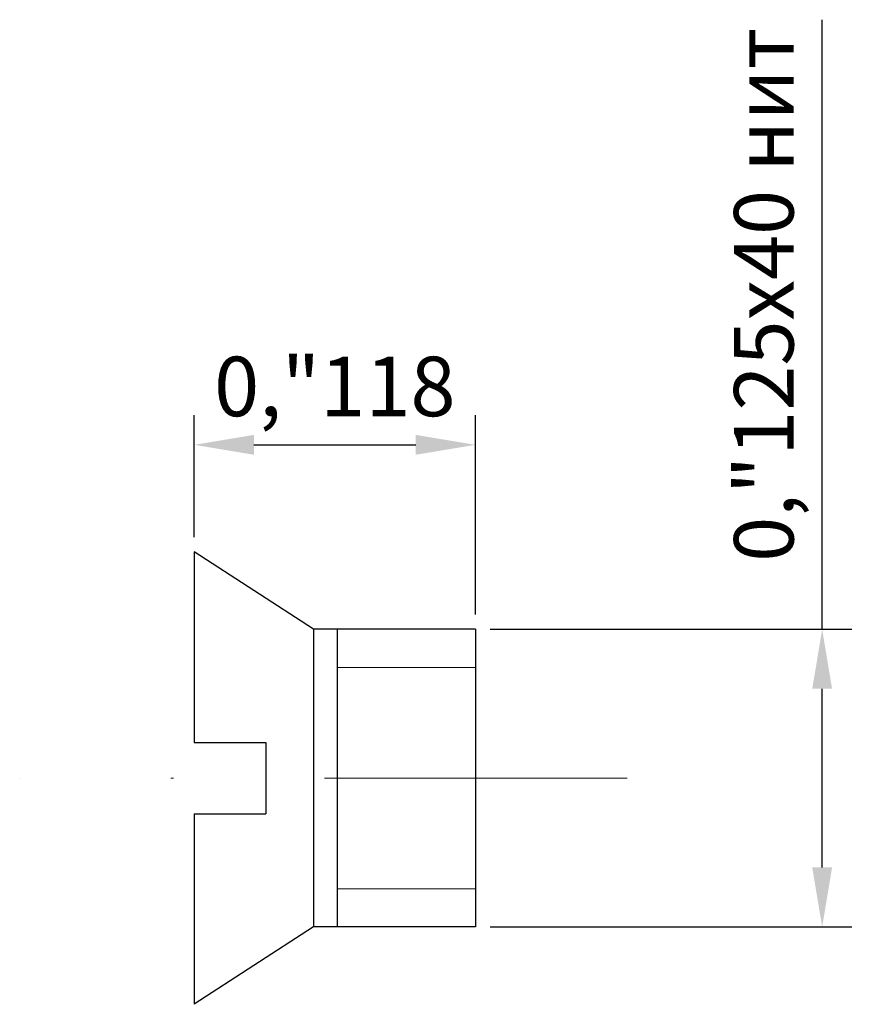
# Model space of a CAD drawing. Units: millimetres. Extents: x -7.3 to 28, y -9.5 to 31.9.
import ezdxf

# ---------------------------------------------------------------- set-up
doc = ezdxf.new("R2010")
doc.units = ezdxf.units.MM
doc.linetypes.add('штрихпунктирная', pattern=[25.4, 12.7, -6.35, 0, -6.35])
doc.styles.get("Standard").update_dxf_attribs({"font": 'ARIAL.TTF'})
doc.dimstyles.new('ISO-25', dxfattribs={"dimtxt": 2.5, "dimasz": 2.5, "dimexe": 1.25, "dimexo": 0.625, "dimtad": 1, "dimtxsty": 'Standard', "dimcen": 2.5, "dimadec": 0, "dimazin": 0, "dimtfac": 1, "dimtmove": 0, "dimatfit": 3, "dimfxl": 0, "dimarcsym": 0})

# ---------------------------------------------------------------- blocks, each defined once
blk = doc.blocks.new('*D2')
at = {"color": 0, "lineweight": -2}
for p, q in [((0, 10.125), (0, 15.247)), ((11.8, 6.875), (11.8, 15.247)), ((2.5, 13.997), (9.3, 13.997))]:
    blk.add_line(p, q, dxfattribs=at)
at = {"color": 0, "lineweight": 9}
for points in [[(2.5, 14.414), (2.5, 13.581), (0, 13.997)], [(9.3, 14.414), (9.3, 13.581), (11.8, 13.997)]]:
    blk.add_solid(points, dxfattribs=at)
at = {"layer": 'Defpoints', "color": 0, "lineweight": 9}
for p in [(11.8, 13.997), (0, 9.5), (11.8, 6.25)]:
    blk.add_point(p, dxfattribs=at)
at = {"color": 0, "lineweight": 9, "insert": (5.9, 16.125), "char_height": 2.5, "attachment_point": 5}
blk.add_mtext('0,"118', dxfattribs=at)
blk = doc.blocks.new('*D3')
at = {"color": 0, "lineweight": -2}
for p, q in [((26.361, 6.25), (26.361, 31.852)), ((12.425, 6.25), (27.611, 6.25)), ((26.361, -3.75), (26.361, 3.75)), ((12.425, -6.25), (27.611, -6.25))]:
    blk.add_line(p, q, dxfattribs=at)
at = {"color": 0, "lineweight": 9}
for points in [[(25.944, 3.75), (26.777, 3.75), (26.361, 6.25)], [(25.944, -3.75), (26.777, -3.75), (26.361, -6.25)]]:
    blk.add_solid(points, dxfattribs=at)
at = {"layer": 'Defpoints', "color": 0, "lineweight": 9}
for p in [(11.8, 6.25), (26.361, 6.25), (11.8, -6.25)]:
    blk.add_point(p, dxfattribs=at)
at = {"color": 0, "lineweight": 9, "insert": (24.233, 20.301), "char_height": 2.5, "attachment_point": 5, "rotation": 90}
blk.add_mtext('0,"125х40 нит', dxfattribs=at)

msp = doc.modelspace()

# ---------------------------------------------------------------- linework, layer by layer
for p, q in [((0, 9.5), (0, 1.5)), ((5, 6.25), (0, 9.5)), ((6, 6.25), (5, 6.25)), ((5, 6.25), (5, -6.25)), ((11.8, 6.25), (6, 6.25)), ((6, 6.25), (6, -6.25)), ((11.8, 6.25), (11.8, -6.25)), ((0, 1.5), (3, 1.5)), ((3, 1.5), (3, -1.5)), ((0, -1.5), (3, -1.5)), ((0, -1.5), (3, -1.5)), ((0, -1.5), (0, -9.5)), ((5, -6.25), (0, -9.5)), ((6, -6.25), (5, -6.25)), ((11.8, -6.25), (6, -6.25))]:
    msp.add_line(p, q)
at = {"lineweight": 9}
for p, q in [((11.8, 4.65), (6, 4.65)), ((11.8, -4.65), (6, -4.65))]:
    msp.add_line(p, q, dxfattribs=at)
at = {"color": 1, "linetype": 'штрихпунктирная', "lineweight": 9}
msp.add_line((18.171, 0), (-7.33, 0), dxfattribs=at)

# ---------------------------------------------------------------- dimensions: what is measured, and where the dimension line sits
at = {"color": 3, "lineweight": 9}
dim = msp.add_linear_dim(base=(26.361, 6.25), p1=(11.8, -6.25), p2=(11.8, 6.25), angle=90, text='0,"125х40 нит', dimstyle='ISO-25', dxfattribs=at)
dim.commit()
dim.dimension.update_dxf_attribs({"geometry": '*D3', "text_midpoint": (24.233, 20.301)})
dim = msp.add_linear_dim(base=(11.8, 13.997), p1=(0, 9.5), p2=(11.8, 6.25), text='0,"118', dimstyle='ISO-25', dxfattribs=at)
dim.commit()
dim.dimension.update_dxf_attribs({"geometry": '*D2', "text_midpoint": (5.9, 16.125)})

doc.saveas('drawing.dxf')
